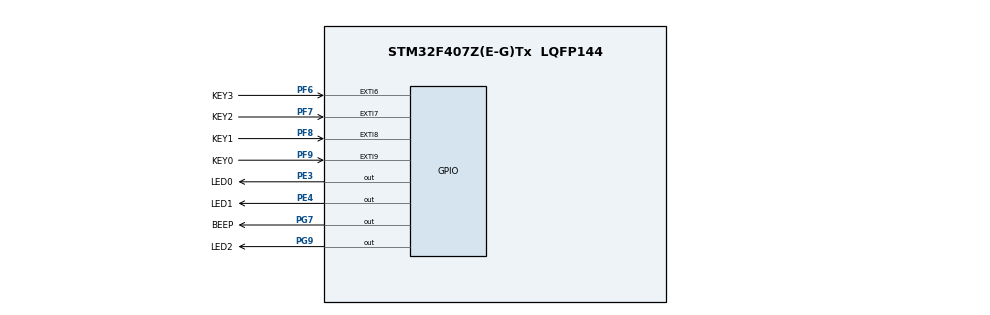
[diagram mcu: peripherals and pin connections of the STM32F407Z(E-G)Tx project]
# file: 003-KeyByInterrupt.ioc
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Mcu.Family=STM32F4
Mcu.Name=STM32F407Z(E-G)Tx
Mcu.Package=LQFP144
NVIC.EXTI9_5_IRQn=true\:0\:0\:false\:false\:true\:true\:true\:true
NVIC.PriorityGroup=NVIC_PRIORITYGROUP_4
PA13.Mode=Serial_Wire
PA13.Signal=SYS_JTMS-SWDIO
PA14.Mode=Serial_Wire
PA14.Signal=SYS_JTCK-SWCLK
PC14-OSC32_IN.Mode=LSE-External-Oscillator
PC14-OSC32_IN.Signal=RCC_OSC32_IN
PC15-OSC32_OUT.Mode=LSE-External-Oscillator
PC15-OSC32_OUT.Signal=RCC_OSC32_OUT
PE3.GPIO_Label=LED0
PE3.PinState=GPIO_PIN_SET
PE3.Signal=GPIO_Output
PE4.GPIO_Label=LED1
PE4.PinState=GPIO_PIN_SET
PE4.Signal=GPIO_Output
PF6.GPIO_Label=KEY3
PF6.GPIO_ModeDefaultEXTI=GPIO_MODE_IT_FALLING
PF6.GPIO_PuPd=GPIO_PULLUP
PF6.Signal=GPXTI6
PF7.GPIO_Label=KEY2
PF7.GPIO_ModeDefaultEXTI=GPIO_MODE_IT_FALLING
PF7.GPIO_PuPd=GPIO_PULLUP
PF7.Signal=GPXTI7
PF8.GPIO_Label=KEY1
PF8.GPIO_ModeDefaultEXTI=GPIO_MODE_IT_FALLING
PF8.GPIO_PuPd=GPIO_PULLUP
PF8.Signal=GPXTI8
PF9.GPIO_Label=KEY0
PF9.GPIO_ModeDefaultEXTI=GPIO_MODE_IT_FALLING
PF9.GPIO_PuPd=GPIO_PULLUP
PF9.Signal=GPXTI9
PG7.GPIO_Label=BEEP
PG7.Signal=GPIO_Output
PG9.GPIO_Label=LED2
PG9.PinState=GPIO_PIN_SET
PG9.Signal=GPIO_Output
PH0-OSC_IN.Mode=HSE-External-Oscillator
PH0-OSC_IN.Signal=RCC_OSC_IN
PH1-OSC_OUT.Mode=HSE-External-Oscillator
PH1-OSC_OUT.Signal=RCC_OSC_OUT
ProjectManager.HeapSize=0x200
ProjectManager.StackSize=0x400
ProjectManager.TargetToolchain=CMake
RCC.48MHZClocksFreq_Value=84000000
RCC.AHBFreq_Value=168000000
RCC.APB1CLKDivider=RCC_HCLK_DIV4
RCC.APB1Freq_Value=42000000
RCC.APB1TimFreq_Value=84000000
RCC.APB2CLKDivider=RCC_HCLK_DIV2
RCC.APB2Freq_Value=84000000
RCC.APB2TimFreq_Value=168000000
RCC.CortexFreq_Value=168000000
RCC.HCLKFreq_Value=168000000
RCC.HSE_VALUE=8000000
RCC.HSI_VALUE=16000000
RCC.PLLM=8
RCC.PLLN=336
RCC.PLLSourceVirtual=RCC_PLLSOURCE_HSE
RCC.SYSCLKFreq_VALUE=168000000
RCC.SYSCLKSource=RCC_SYSCLKSOURCE_PLLCLK
RCC.VCOOutputFreq_Value=336000000
board=custom

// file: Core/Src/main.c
/* USER CODE BEGIN Header */
/**
  ******************************************************************************
  * @file           : main.c
  * @brief          : Main program body
  ******************************************************************************
  * @attention
  *
  * Copyright (c) 2026 STMicroelectronics.
  * All rights reserved.
  *
  * This software is licensed under terms that can be found in the LICENSE file
  * in the root directory of this software component.
  * If no LICENSE file comes with this software, it is provided AS-IS.
  *
  ******************************************************************************
  */
/* USER CODE END Header */
#include "main.h"
#include "gpio.h"

/* USER CODE BEGIN PV */
/* 记录上次有效按键触发的时间戳（tick），用于消抖 */
volatile uint32_t g_last_key_tick = 0;
/* USER CODE END PV */

void SystemClock_Config(void);

int main(void)
{

  /* MCU Configuration--------------------------------------------------------*/

  /* Reset of all peripherals, Initializes the Flash interface and the Systick. */
  HAL_Init();

  /* Configure the system clock */
  SystemClock_Config();

  /* Initialize all configured peripherals */
  MX_GPIO_Init();

  /* Infinite loop */
  while (1)
  {

  }
}

void SystemClock_Config(void)
{
  RCC_OscInitTypeDef RCC_OscInitStruct = {0};
  RCC_ClkInitTypeDef RCC_ClkInitStruct = {0};

  /** Configure the main internal regulator output voltage
  */
  __HAL_RCC_PWR_CLK_ENABLE();
  __HAL_PWR_VOLTAGESCALING_CONFIG(PWR_REGULATOR_VOLTAGE_SCALE1);

  /** Initializes the RCC Oscillators according to the specified parameters
  * in the RCC_OscInitTypeDef structure.
  */
  RCC_OscInitStruct.OscillatorType = RCC_OSCILLATORTYPE_HSE;
  RCC_OscInitStruct.HSEState = RCC_HSE_ON;
  RCC_OscInitStruct.PLL.PLLState = RCC_PLL_ON;
  RCC_OscInitStruct.PLL.PLLSource = RCC_PLLSOURCE_HSE;
  RCC_OscInitStruct.PLL.PLLM = 25;
  RCC_OscInitStruct.PLL.PLLN = 336;
  RCC_OscInitStruct.PLL.PLLP = RCC_PLLP_DIV2;
  RCC_OscInitStruct.PLL.PLLQ = 4;
  if (HAL_RCC_OscConfig(&RCC_OscInitStruct) != HAL_OK)
  {
    Error_Handler();
  }

  /** Initializes the CPU, AHB and APB buses clocks
  */
  RCC_ClkInitStruct.ClockType = RCC_CLOCKTYPE_HCLK|RCC_CLOCKTYPE_SYSCLK
                              |RCC_CLOCKTYPE_PCLK1|RCC_CLOCKTYPE_PCLK2;
  RCC_ClkInitStruct.SYSCLKSource = RCC_SYSCLKSOURCE_PLLCLK;
  RCC_ClkInitStruct.AHBCLKDivider = RCC_SYSCLK_DIV1;
  RCC_ClkInitStruct.APB1CLKDivider = RCC_HCLK_DIV4;
  RCC_ClkInitStruct.APB2CLKDivider = RCC_HCLK_DIV2;

  if (HAL_RCC_ClockConfig(&RCC_ClkInitStruct, FLASH_LATENCY_5) != HAL_OK)
  {
    Error_Handler();
  }
}

/* USER CODE BEGIN 4 */
#define KEY_DEBOUNCE_MS 20

void HAL_GPIO_EXTI_Callback(uint16_t GPIO_Pin)
{
  /* 方式三：基于时间戳的非阻塞消抖
   * 中断里不做阻塞延时，只判断两次触发的时间间隔。
   * 若间隔小于阈值（抖动）则忽略，避免干扰 EXTI 高优先级中断。 */
  uint32_t now = HAL_GetTick();
  if ((now - g_last_key_tick) < KEY_DEBOUNCE_MS)
  {
    return; /* 抖动，忽略本次触发 */
  }
  g_last_key_tick = now;

  if(GPIO_Pin == KEY0_Pin)
  {
    HAL_GPIO_WritePin(LED0_GPIO_Port, LED0_Pin, GPIO_PIN_SET);
  }
  else if(GPIO_Pin == KEY1_Pin)
  {
    HAL_GPIO_WritePin(LED0_GPIO_Port, LED0_Pin, GPIO_PIN_RESET);
  }
  else if(GPIO_Pin == KEY2_Pin)
  {
    HAL_GPIO_TogglePin(LED2_GPIO_Port, LED2_Pin);
  }
  else if(GPIO_Pin == KEY3_Pin)
  {
    HAL_GPIO_TogglePin(LED1_GPIO_Port, LED1_Pin);
  }
}
/* USER CODE END 4 */

void Error_Handler(void)
{
  __disable_irq();
  while (1)
  {
  }
}
